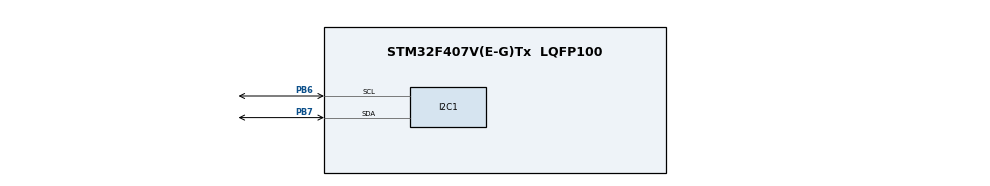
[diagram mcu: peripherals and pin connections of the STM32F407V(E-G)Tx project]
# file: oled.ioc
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Mcu.Family=STM32F4
RCC.VCOOutputFreq_Value=192000000
RCC.APB2Freq_Value=16000000
RCC.CortexFreq_Value=16000000
PB7.Signal=I2C1_SDA
Mcu.Name=STM32F407V(E-G)Tx
RCC.SYSCLKFreq_VALUE=16000000
Mcu.Package=LQFP100
ProjectManager.StackSize=0x400
PB7.Mode=I2C
ProjectManager.HeapSize=0x200
ProjectManager.TargetToolchain=STM32CubeIDE
RCC.HSI_VALUE=16000000
I2C1.I2C_Mode=I2C_Fast
NVIC.PriorityGroup=NVIC_PRIORITYGROUP_4
PB6.Signal=I2C1_SCL
PB6.Mode=I2C
RCC.APB1Freq_Value=16000000
RCC.LSE_VALUE=32768
RCC.AHBFreq_Value=16000000
RCC.HSE_VALUE=25000000
board=custom

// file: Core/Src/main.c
/* USER CODE BEGIN Header */
/**
  ******************************************************************************
  * @file           : main.c
  * @brief          : Main program body
  ******************************************************************************
  * @attention
  *
  * <h2><center>&copy; Copyright (c) 2021 STMicroelectronics.
  * All rights reserved.</center></h2>
  *
  * This software component is licensed by ST under BSD 3-Clause license,
  * the "License"; You may not use this file except in compliance with the
  * License. You may obtain a copy of the License at:
  *                        opensource.org/licenses/BSD-3-Clause
  *
  ******************************************************************************
  */
/* USER CODE END Header */
#include "main.h"
#include "i2c-lcd.h"
#include "ssd1306.h"
#include "fonts.h"
#include "string.h"
#include "stdio.h"

I2C_HandleTypeDef hi2c1;

void SystemClock_Config(void);
static void MX_GPIO_Init(void);
static void MX_I2C1_Init(void);
/* USER CODE BEGIN PFP */
char txt[50]; // ekrandaki metnin tutulduğu değişken.
uint8_t check; //kontrol değişkeni
int vout = 95;
/* USER CODE END PFP */

int main(void)
{

  /* MCU Configuration--------------------------------------------------------*/

  /* Reset of all peripherals, Initializes the Flash interface and the Systick. */
  HAL_Init();

  /* Configure the system clock */
  SystemClock_Config();

  /* Initialize all configured peripherals */
  MX_GPIO_Init();
  MX_I2C1_Init();
  /* USER CODE BEGIN 2 */

  // Ekranın Temizlenip aktif edilmesi.
  	  	lcd_init ();
    	check = ssd1306_Init();
    	ssd1306_Fill(0);
    	ssd1306_UpdateScreen();
    	HAL_Delay(20);
  /* USER CODE END 2 */

  /* Infinite loop */
  while (1)
  {

    /* USER CODE BEGIN 3 */
	      ssd1306_Fill(Black);
	  	  ssd1306_SetCursor(0,15); // Ekrandaki Koordinat yerleri
	  	  sprintf(txt,"ELTAGRON");
	  	  ssd1306_WriteString(txt,Font_11x18,White);
	  	  ssd1306_UpdateScreen();
	  	  HAL_Delay(500);
  }
  /* USER CODE END 3 */
}

void SystemClock_Config(void)
{
  RCC_OscInitTypeDef RCC_OscInitStruct = {0};
  RCC_ClkInitTypeDef RCC_ClkInitStruct = {0};

  /** Configure the main internal regulator output voltage
  */
  __HAL_RCC_PWR_CLK_ENABLE();
  __HAL_PWR_VOLTAGESCALING_CONFIG(PWR_REGULATOR_VOLTAGE_SCALE1);
  /** Initializes the RCC Oscillators according to the specified parameters
  * in the RCC_OscInitTypeDef structure.
  */
  RCC_OscInitStruct.OscillatorType = RCC_OSCILLATORTYPE_HSI;
  RCC_OscInitStruct.HSIState = RCC_HSI_ON;
  RCC_OscInitStruct.HSICalibrationValue = RCC_HSICALIBRATION_DEFAULT;
  RCC_OscInitStruct.PLL.PLLState = RCC_PLL_ON;
  RCC_OscInitStruct.PLL.PLLSource = RCC_PLLSOURCE_HSI;
  RCC_OscInitStruct.PLL.PLLM = 8;
  RCC_OscInitStruct.PLL.PLLN = 168;
  RCC_OscInitStruct.PLL.PLLP = RCC_PLLP_DIV2;
  RCC_OscInitStruct.PLL.PLLQ = 4;
  if (HAL_RCC_OscConfig(&RCC_OscInitStruct) != HAL_OK)
  {
    Error_Handler();
  }
  /** Initializes the CPU, AHB and APB buses clocks
  */
  RCC_ClkInitStruct.ClockType = RCC_CLOCKTYPE_HCLK|RCC_CLOCKTYPE_SYSCLK
                              |RCC_CLOCKTYPE_PCLK1|RCC_CLOCKTYPE_PCLK2;
  RCC_ClkInitStruct.SYSCLKSource = RCC_SYSCLKSOURCE_PLLCLK;
  RCC_ClkInitStruct.AHBCLKDivider = RCC_SYSCLK_DIV1;
  RCC_ClkInitStruct.APB1CLKDivider = RCC_HCLK_DIV4;
  RCC_ClkInitStruct.APB2CLKDivider = RCC_HCLK_DIV2;

  if (HAL_RCC_ClockConfig(&RCC_ClkInitStruct, FLASH_LATENCY_5) != HAL_OK)
  {
    Error_Handler();
  }
}

static void MX_I2C1_Init(void)
{

  hi2c1.Instance = I2C1;
  hi2c1.Init.ClockSpeed = 400000;
  hi2c1.Init.DutyCycle = I2C_DUTYCYCLE_2;
  hi2c1.Init.OwnAddress1 = 0;
  hi2c1.Init.AddressingMode = I2C_ADDRESSINGMODE_7BIT;
  hi2c1.Init.DualAddressMode = I2C_DUALADDRESS_DISABLE;
  hi2c1.Init.OwnAddress2 = 0;
  hi2c1.Init.GeneralCallMode = I2C_GENERALCALL_DISABLE;
  hi2c1.Init.NoStretchMode = I2C_NOSTRETCH_DISABLE;
  if (HAL_I2C_Init(&hi2c1) != HAL_OK)
  {
    Error_Handler();
  }

}

static void MX_GPIO_Init(void)
{

  /* GPIO Ports Clock Enable */
  __HAL_RCC_GPIOB_CLK_ENABLE();

}

void Error_Handler(void)
{
  __disable_irq();
  while (1)
  {
  }
}

/************************ (C) COPYRIGHT STMicroelectronics *****END OF FILE****/
